VERSION 5.7 ;
  NOWIREEXTENSIONATPIN ON ;
  DIVIDERCHAR "/" ;
  BUSBITCHARS "[]" ;
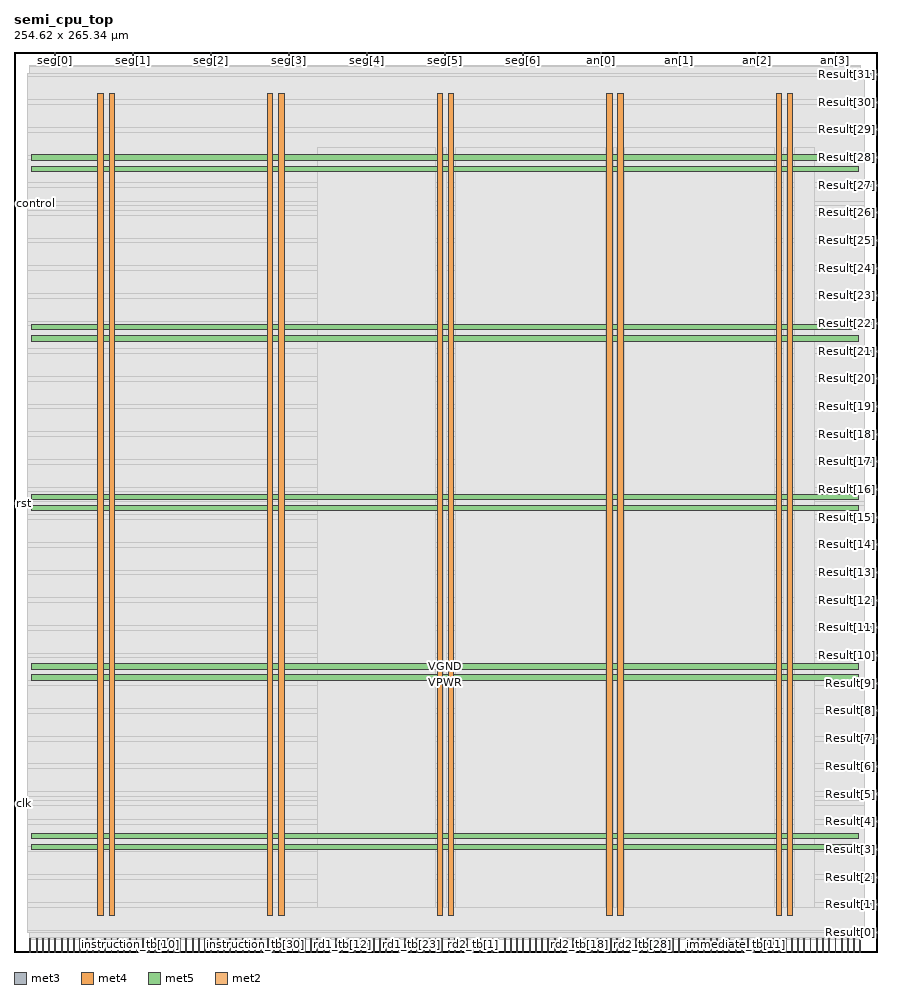
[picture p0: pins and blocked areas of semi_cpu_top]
MACRO semi_cpu_top
  CLASS BLOCK ;
  FOREIGN semi_cpu_top ;
  ORIGIN 0.000 0.000 ;
  SIZE 254.620 BY 265.340 ;
  PIN Result[0]
    DIRECTION OUTPUT ;
    USE SIGNAL ;
    ANTENNADIFFAREA 0.445500 ;
    PORT
      LAYER met3 ;
        RECT 250.620 5.480 254.620 6.080 ;
    END
  END Result[0]
  PIN Result[10]
    DIRECTION OUTPUT ;
    USE SIGNAL ;
    ANTENNADIFFAREA 0.445500 ;
    PORT
      LAYER met3 ;
        RECT 250.620 87.080 254.620 87.680 ;
    END
  END Result[10]
  PIN Result[11]
    DIRECTION OUTPUT ;
    USE SIGNAL ;
    ANTENNADIFFAREA 0.445500 ;
    PORT
      LAYER met3 ;
        RECT 250.620 95.240 254.620 95.840 ;
    END
  END Result[11]
  PIN Result[12]
    DIRECTION OUTPUT ;
    USE SIGNAL ;
    ANTENNADIFFAREA 0.445500 ;
    PORT
      LAYER met3 ;
        RECT 250.620 103.400 254.620 104.000 ;
    END
  END Result[12]
  PIN Result[13]
    DIRECTION OUTPUT ;
    USE SIGNAL ;
    ANTENNADIFFAREA 0.445500 ;
    PORT
      LAYER met3 ;
        RECT 250.620 111.560 254.620 112.160 ;
    END
  END Result[13]
  PIN Result[14]
    DIRECTION OUTPUT ;
    USE SIGNAL ;
    ANTENNADIFFAREA 0.445500 ;
    PORT
      LAYER met3 ;
        RECT 250.620 119.720 254.620 120.320 ;
    END
  END Result[14]
  PIN Result[15]
    DIRECTION OUTPUT ;
    USE SIGNAL ;
    ANTENNADIFFAREA 0.445500 ;
    PORT
      LAYER met3 ;
        RECT 250.620 127.880 254.620 128.480 ;
    END
  END Result[15]
  PIN Result[16]
    DIRECTION OUTPUT ;
    USE SIGNAL ;
    ANTENNADIFFAREA 0.445500 ;
    PORT
      LAYER met3 ;
        RECT 250.620 136.040 254.620 136.640 ;
    END
  END Result[16]
  PIN Result[17]
    DIRECTION OUTPUT ;
    USE SIGNAL ;
    ANTENNADIFFAREA 0.445500 ;
    PORT
      LAYER met3 ;
        RECT 250.620 144.200 254.620 144.800 ;
    END
  END Result[17]
  PIN Result[18]
    DIRECTION OUTPUT ;
    USE SIGNAL ;
    ANTENNADIFFAREA 0.445500 ;
    PORT
      LAYER met3 ;
        RECT 250.620 152.360 254.620 152.960 ;
    END
  END Result[18]
  PIN Result[19]
    DIRECTION OUTPUT ;
    USE SIGNAL ;
    ANTENNADIFFAREA 0.445500 ;
    PORT
      LAYER met3 ;
        RECT 250.620 160.520 254.620 161.120 ;
    END
  END Result[19]
  PIN Result[1]
    DIRECTION OUTPUT ;
    USE SIGNAL ;
    ANTENNADIFFAREA 0.445500 ;
    PORT
      LAYER met3 ;
        RECT 250.620 13.640 254.620 14.240 ;
    END
  END Result[1]
  PIN Result[20]
    DIRECTION OUTPUT ;
    USE SIGNAL ;
    ANTENNADIFFAREA 0.445500 ;
    PORT
      LAYER met3 ;
        RECT 250.620 168.680 254.620 169.280 ;
    END
  END Result[20]
  PIN Result[21]
    DIRECTION OUTPUT ;
    USE SIGNAL ;
    ANTENNADIFFAREA 0.445500 ;
    PORT
      LAYER met3 ;
        RECT 250.620 176.840 254.620 177.440 ;
    END
  END Result[21]
  PIN Result[22]
    DIRECTION OUTPUT ;
    USE SIGNAL ;
    ANTENNADIFFAREA 0.445500 ;
    PORT
      LAYER met3 ;
        RECT 250.620 185.000 254.620 185.600 ;
    END
  END Result[22]
  PIN Result[23]
    DIRECTION OUTPUT ;
    USE SIGNAL ;
    ANTENNADIFFAREA 0.445500 ;
    PORT
      LAYER met3 ;
        RECT 250.620 193.160 254.620 193.760 ;
    END
  END Result[23]
  PIN Result[24]
    DIRECTION OUTPUT ;
    USE SIGNAL ;
    ANTENNADIFFAREA 0.445500 ;
    PORT
      LAYER met3 ;
        RECT 250.620 201.320 254.620 201.920 ;
    END
  END Result[24]
  PIN Result[25]
    DIRECTION OUTPUT ;
    USE SIGNAL ;
    ANTENNADIFFAREA 0.445500 ;
    PORT
      LAYER met3 ;
        RECT 250.620 209.480 254.620 210.080 ;
    END
  END Result[25]
  PIN Result[26]
    DIRECTION OUTPUT ;
    USE SIGNAL ;
    ANTENNADIFFAREA 0.445500 ;
    PORT
      LAYER met3 ;
        RECT 250.620 217.640 254.620 218.240 ;
    END
  END Result[26]
  PIN Result[27]
    DIRECTION OUTPUT ;
    USE SIGNAL ;
    ANTENNADIFFAREA 0.445500 ;
    PORT
      LAYER met3 ;
        RECT 250.620 225.800 254.620 226.400 ;
    END
  END Result[27]
  PIN Result[28]
    DIRECTION OUTPUT ;
    USE SIGNAL ;
    ANTENNADIFFAREA 0.445500 ;
    PORT
      LAYER met3 ;
        RECT 250.620 233.960 254.620 234.560 ;
    END
  END Result[28]
  PIN Result[29]
    DIRECTION OUTPUT ;
    USE SIGNAL ;
    ANTENNADIFFAREA 0.445500 ;
    PORT
      LAYER met3 ;
        RECT 250.620 242.120 254.620 242.720 ;
    END
  END Result[29]
  PIN Result[2]
    DIRECTION OUTPUT ;
    USE SIGNAL ;
    ANTENNADIFFAREA 0.445500 ;
    PORT
      LAYER met3 ;
        RECT 250.620 21.800 254.620 22.400 ;
    END
  END Result[2]
  PIN Result[30]
    DIRECTION OUTPUT ;
    USE SIGNAL ;
    ANTENNADIFFAREA 0.445500 ;
    PORT
      LAYER met3 ;
        RECT 250.620 250.280 254.620 250.880 ;
    END
  END Result[30]
  PIN Result[31]
    DIRECTION OUTPUT ;
    USE SIGNAL ;
    ANTENNADIFFAREA 0.445500 ;
    PORT
      LAYER met3 ;
        RECT 250.620 258.440 254.620 259.040 ;
    END
  END Result[31]
  PIN Result[3]
    DIRECTION OUTPUT ;
    USE SIGNAL ;
    ANTENNADIFFAREA 0.445500 ;
    PORT
      LAYER met3 ;
        RECT 250.620 29.960 254.620 30.560 ;
    END
  END Result[3]
  PIN Result[4]
    DIRECTION OUTPUT ;
    USE SIGNAL ;
    ANTENNADIFFAREA 0.445500 ;
    PORT
      LAYER met3 ;
        RECT 250.620 38.120 254.620 38.720 ;
    END
  END Result[4]
  PIN Result[5]
    DIRECTION OUTPUT ;
    USE SIGNAL ;
    ANTENNADIFFAREA 0.445500 ;
    PORT
      LAYER met3 ;
        RECT 250.620 46.280 254.620 46.880 ;
    END
  END Result[5]
  PIN Result[6]
    DIRECTION OUTPUT ;
    USE SIGNAL ;
    ANTENNADIFFAREA 0.445500 ;
    PORT
      LAYER met3 ;
        RECT 250.620 54.440 254.620 55.040 ;
    END
  END Result[6]
  PIN Result[7]
    DIRECTION OUTPUT ;
    USE SIGNAL ;
    ANTENNADIFFAREA 0.445500 ;
    PORT
      LAYER met3 ;
        RECT 250.620 62.600 254.620 63.200 ;
    END
  END Result[7]
  PIN Result[8]
    DIRECTION OUTPUT ;
    USE SIGNAL ;
    ANTENNADIFFAREA 0.445500 ;
    PORT
      LAYER met3 ;
        RECT 250.620 70.760 254.620 71.360 ;
    END
  END Result[8]
  PIN Result[9]
    DIRECTION OUTPUT ;
    USE SIGNAL ;
    ANTENNADIFFAREA 0.445500 ;
    PORT
      LAYER met3 ;
        RECT 250.620 78.920 254.620 79.520 ;
    END
  END Result[9]
  PIN VGND
    DIRECTION INOUT ;
    USE GROUND ;
    PORT
      LAYER met4 ;
        RECT 28.020 10.640 29.620 253.200 ;
    END
    PORT
      LAYER met4 ;
        RECT 78.020 10.640 79.620 253.200 ;
    END
    PORT
      LAYER met4 ;
        RECT 128.020 10.640 129.620 253.200 ;
    END
    PORT
      LAYER met4 ;
        RECT 178.020 10.640 179.620 253.200 ;
    END
    PORT
      LAYER met4 ;
        RECT 228.020 10.640 229.620 253.200 ;
    END
    PORT
      LAYER met5 ;
        RECT 5.280 33.380 249.100 34.980 ;
    END
    PORT
      LAYER met5 ;
        RECT 5.280 83.380 249.100 84.980 ;
    END
    PORT
      LAYER met5 ;
        RECT 5.280 133.380 249.100 134.980 ;
    END
    PORT
      LAYER met5 ;
        RECT 5.280 183.380 249.100 184.980 ;
    END
    PORT
      LAYER met5 ;
        RECT 5.280 233.380 249.100 234.980 ;
    END
  END VGND
  PIN VPWR
    DIRECTION INOUT ;
    USE POWER ;
    PORT
      LAYER met4 ;
        RECT 24.720 10.640 26.320 253.200 ;
    END
    PORT
      LAYER met4 ;
        RECT 74.720 10.640 76.320 253.200 ;
    END
    PORT
      LAYER met4 ;
        RECT 124.720 10.640 126.320 253.200 ;
    END
    PORT
      LAYER met4 ;
        RECT 174.720 10.640 176.320 253.200 ;
    END
    PORT
      LAYER met4 ;
        RECT 224.720 10.640 226.320 253.200 ;
    END
    PORT
      LAYER met5 ;
        RECT 5.280 30.080 249.100 31.680 ;
    END
    PORT
      LAYER met5 ;
        RECT 5.280 80.080 249.100 81.680 ;
    END
    PORT
      LAYER met5 ;
        RECT 5.280 130.080 249.100 131.680 ;
    END
    PORT
      LAYER met5 ;
        RECT 5.280 180.080 249.100 181.680 ;
    END
    PORT
      LAYER met5 ;
        RECT 5.280 230.080 249.100 231.680 ;
    END
  END VPWR
  PIN alu_op_tb[0]
    DIRECTION OUTPUT ;
    USE SIGNAL ;
    ANTENNADIFFAREA 0.445500 ;
    PORT
      LAYER met2 ;
        RECT 10.210 0.000 10.490 4.000 ;
    END
  END alu_op_tb[0]
  PIN alu_op_tb[1]
    DIRECTION OUTPUT ;
    USE SIGNAL ;
    ANTENNADIFFAREA 0.445500 ;
    PORT
      LAYER met2 ;
        RECT 12.050 0.000 12.330 4.000 ;
    END
  END alu_op_tb[1]
  PIN alu_op_tb[2]
    DIRECTION OUTPUT ;
    USE SIGNAL ;
    ANTENNADIFFAREA 0.445500 ;
    PORT
      LAYER met2 ;
        RECT 13.890 0.000 14.170 4.000 ;
    END
  END alu_op_tb[2]
  PIN an[0]
    DIRECTION OUTPUT ;
    USE SIGNAL ;
    ANTENNADIFFAREA 0.795200 ;
    PORT
      LAYER met2 ;
        RECT 173.050 261.340 173.330 265.340 ;
    END
  END an[0]
  PIN an[1]
    DIRECTION OUTPUT ;
    USE SIGNAL ;
    ANTENNADIFFAREA 0.795200 ;
    PORT
      LAYER met2 ;
        RECT 196.050 261.340 196.330 265.340 ;
    END
  END an[1]
  PIN an[2]
    DIRECTION OUTPUT ;
    USE SIGNAL ;
    ANTENNADIFFAREA 0.795200 ;
    PORT
      LAYER met2 ;
        RECT 219.050 261.340 219.330 265.340 ;
    END
  END an[2]
  PIN an[3]
    DIRECTION OUTPUT ;
    USE SIGNAL ;
    ANTENNADIFFAREA 0.795200 ;
    PORT
      LAYER met2 ;
        RECT 242.050 261.340 242.330 265.340 ;
    END
  END an[3]
  PIN clk
    DIRECTION INPUT ;
    USE SIGNAL ;
    ANTENNAGATEAREA 0.852000 ;
    ANTENNADIFFAREA 0.434700 ;
    PORT
      LAYER met3 ;
        RECT 0.000 43.560 4.000 44.160 ;
    END
  END clk
  PIN control
    DIRECTION INPUT ;
    USE SIGNAL ;
    ANTENNAGATEAREA 0.495000 ;
    ANTENNADIFFAREA 0.434700 ;
    PORT
      LAYER met3 ;
        RECT 0.000 220.360 4.000 220.960 ;
    END
  END control
  PIN immediate_tb[0]
    DIRECTION OUTPUT ;
    USE SIGNAL ;
    ANTENNADIFFAREA 0.445500 ;
    PORT
      LAYER met2 ;
        RECT 192.370 0.000 192.650 4.000 ;
    END
  END immediate_tb[0]
  PIN immediate_tb[10]
    DIRECTION OUTPUT ;
    USE SIGNAL ;
    PORT
      LAYER met2 ;
        RECT 210.770 0.000 211.050 4.000 ;
    END
  END immediate_tb[10]
  PIN immediate_tb[11]
    DIRECTION OUTPUT ;
    USE SIGNAL ;
    PORT
      LAYER met2 ;
        RECT 212.610 0.000 212.890 4.000 ;
    END
  END immediate_tb[11]
  PIN immediate_tb[12]
    DIRECTION OUTPUT ;
    USE SIGNAL ;
    PORT
      LAYER met2 ;
        RECT 214.450 0.000 214.730 4.000 ;
    END
  END immediate_tb[12]
  PIN immediate_tb[13]
    DIRECTION OUTPUT ;
    USE SIGNAL ;
    PORT
      LAYER met2 ;
        RECT 216.290 0.000 216.570 4.000 ;
    END
  END immediate_tb[13]
  PIN immediate_tb[14]
    DIRECTION OUTPUT ;
    USE SIGNAL ;
    ANTENNADIFFAREA 0.445500 ;
    PORT
      LAYER met2 ;
        RECT 218.130 0.000 218.410 4.000 ;
    END
  END immediate_tb[14]
  PIN immediate_tb[15]
    DIRECTION OUTPUT ;
    USE SIGNAL ;
    ANTENNADIFFAREA 0.445500 ;
    PORT
      LAYER met2 ;
        RECT 219.970 0.000 220.250 4.000 ;
    END
  END immediate_tb[15]
  PIN immediate_tb[16]
    DIRECTION OUTPUT ;
    USE SIGNAL ;
    PORT
      LAYER met2 ;
        RECT 221.810 0.000 222.090 4.000 ;
    END
  END immediate_tb[16]
  PIN immediate_tb[17]
    DIRECTION OUTPUT ;
    USE SIGNAL ;
    PORT
      LAYER met2 ;
        RECT 223.650 0.000 223.930 4.000 ;
    END
  END immediate_tb[17]
  PIN immediate_tb[18]
    DIRECTION OUTPUT ;
    USE SIGNAL ;
    PORT
      LAYER met2 ;
        RECT 225.490 0.000 225.770 4.000 ;
    END
  END immediate_tb[18]
  PIN immediate_tb[19]
    DIRECTION OUTPUT ;
    USE SIGNAL ;
    PORT
      LAYER met2 ;
        RECT 227.330 0.000 227.610 4.000 ;
    END
  END immediate_tb[19]
  PIN immediate_tb[1]
    DIRECTION OUTPUT ;
    USE SIGNAL ;
    ANTENNADIFFAREA 0.445500 ;
    PORT
      LAYER met2 ;
        RECT 194.210 0.000 194.490 4.000 ;
    END
  END immediate_tb[1]
  PIN immediate_tb[20]
    DIRECTION OUTPUT ;
    USE SIGNAL ;
    PORT
      LAYER met2 ;
        RECT 229.170 0.000 229.450 4.000 ;
    END
  END immediate_tb[20]
  PIN immediate_tb[21]
    DIRECTION OUTPUT ;
    USE SIGNAL ;
    PORT
      LAYER met2 ;
        RECT 231.010 0.000 231.290 4.000 ;
    END
  END immediate_tb[21]
  PIN immediate_tb[22]
    DIRECTION OUTPUT ;
    USE SIGNAL ;
    PORT
      LAYER met2 ;
        RECT 232.850 0.000 233.130 4.000 ;
    END
  END immediate_tb[22]
  PIN immediate_tb[23]
    DIRECTION OUTPUT ;
    USE SIGNAL ;
    PORT
      LAYER met2 ;
        RECT 234.690 0.000 234.970 4.000 ;
    END
  END immediate_tb[23]
  PIN immediate_tb[24]
    DIRECTION OUTPUT ;
    USE SIGNAL ;
    PORT
      LAYER met2 ;
        RECT 236.530 0.000 236.810 4.000 ;
    END
  END immediate_tb[24]
  PIN immediate_tb[25]
    DIRECTION OUTPUT ;
    USE SIGNAL ;
    PORT
      LAYER met2 ;
        RECT 238.370 0.000 238.650 4.000 ;
    END
  END immediate_tb[25]
  PIN immediate_tb[26]
    DIRECTION OUTPUT ;
    USE SIGNAL ;
    PORT
      LAYER met2 ;
        RECT 240.210 0.000 240.490 4.000 ;
    END
  END immediate_tb[26]
  PIN immediate_tb[27]
    DIRECTION OUTPUT ;
    USE SIGNAL ;
    PORT
      LAYER met2 ;
        RECT 242.050 0.000 242.330 4.000 ;
    END
  END immediate_tb[27]
  PIN immediate_tb[28]
    DIRECTION OUTPUT ;
    USE SIGNAL ;
    PORT
      LAYER met2 ;
        RECT 243.890 0.000 244.170 4.000 ;
    END
  END immediate_tb[28]
  PIN immediate_tb[29]
    DIRECTION OUTPUT ;
    USE SIGNAL ;
    PORT
      LAYER met2 ;
        RECT 245.730 0.000 246.010 4.000 ;
    END
  END immediate_tb[29]
  PIN immediate_tb[2]
    DIRECTION OUTPUT ;
    USE SIGNAL ;
    ANTENNADIFFAREA 0.445500 ;
    PORT
      LAYER met2 ;
        RECT 196.050 0.000 196.330 4.000 ;
    END
  END immediate_tb[2]
  PIN immediate_tb[30]
    DIRECTION OUTPUT ;
    USE SIGNAL ;
    PORT
      LAYER met2 ;
        RECT 247.570 0.000 247.850 4.000 ;
    END
  END immediate_tb[30]
  PIN immediate_tb[31]
    DIRECTION OUTPUT ;
    USE SIGNAL ;
    PORT
      LAYER met2 ;
        RECT 249.410 0.000 249.690 4.000 ;
    END
  END immediate_tb[31]
  PIN immediate_tb[3]
    DIRECTION OUTPUT ;
    USE SIGNAL ;
    ANTENNADIFFAREA 0.445500 ;
    PORT
      LAYER met2 ;
        RECT 197.890 0.000 198.170 4.000 ;
    END
  END immediate_tb[3]
  PIN immediate_tb[4]
    DIRECTION OUTPUT ;
    USE SIGNAL ;
    PORT
      LAYER met2 ;
        RECT 199.730 0.000 200.010 4.000 ;
    END
  END immediate_tb[4]
  PIN immediate_tb[5]
    DIRECTION OUTPUT ;
    USE SIGNAL ;
    PORT
      LAYER met2 ;
        RECT 201.570 0.000 201.850 4.000 ;
    END
  END immediate_tb[5]
  PIN immediate_tb[6]
    DIRECTION OUTPUT ;
    USE SIGNAL ;
    PORT
      LAYER met2 ;
        RECT 203.410 0.000 203.690 4.000 ;
    END
  END immediate_tb[6]
  PIN immediate_tb[7]
    DIRECTION OUTPUT ;
    USE SIGNAL ;
    PORT
      LAYER met2 ;
        RECT 205.250 0.000 205.530 4.000 ;
    END
  END immediate_tb[7]
  PIN immediate_tb[8]
    DIRECTION OUTPUT ;
    USE SIGNAL ;
    PORT
      LAYER met2 ;
        RECT 207.090 0.000 207.370 4.000 ;
    END
  END immediate_tb[8]
  PIN immediate_tb[9]
    DIRECTION OUTPUT ;
    USE SIGNAL ;
    PORT
      LAYER met2 ;
        RECT 208.930 0.000 209.210 4.000 ;
    END
  END immediate_tb[9]
  PIN instruction_tb[0]
    DIRECTION OUTPUT ;
    USE SIGNAL ;
    ANTENNADIFFAREA 0.445500 ;
    PORT
      LAYER met2 ;
        RECT 15.730 0.000 16.010 4.000 ;
    END
  END instruction_tb[0]
  PIN instruction_tb[10]
    DIRECTION OUTPUT ;
    USE SIGNAL ;
    PORT
      LAYER met2 ;
        RECT 34.130 0.000 34.410 4.000 ;
    END
  END instruction_tb[10]
  PIN instruction_tb[11]
    DIRECTION OUTPUT ;
    USE SIGNAL ;
    PORT
      LAYER met2 ;
        RECT 35.970 0.000 36.250 4.000 ;
    END
  END instruction_tb[11]
  PIN instruction_tb[12]
    DIRECTION OUTPUT ;
    USE SIGNAL ;
    PORT
      LAYER met2 ;
        RECT 37.810 0.000 38.090 4.000 ;
    END
  END instruction_tb[12]
  PIN instruction_tb[13]
    DIRECTION OUTPUT ;
    USE SIGNAL ;
    PORT
      LAYER met2 ;
        RECT 39.650 0.000 39.930 4.000 ;
    END
  END instruction_tb[13]
  PIN instruction_tb[14]
    DIRECTION OUTPUT ;
    USE SIGNAL ;
    ANTENNADIFFAREA 0.445500 ;
    PORT
      LAYER met2 ;
        RECT 41.490 0.000 41.770 4.000 ;
    END
  END instruction_tb[14]
  PIN instruction_tb[15]
    DIRECTION OUTPUT ;
    USE SIGNAL ;
    ANTENNADIFFAREA 0.445500 ;
    PORT
      LAYER met2 ;
        RECT 43.330 0.000 43.610 4.000 ;
    END
  END instruction_tb[15]
  PIN instruction_tb[16]
    DIRECTION OUTPUT ;
    USE SIGNAL ;
    ANTENNADIFFAREA 0.445500 ;
    PORT
      LAYER met2 ;
        RECT 45.170 0.000 45.450 4.000 ;
    END
  END instruction_tb[16]
  PIN instruction_tb[17]
    DIRECTION OUTPUT ;
    USE SIGNAL ;
    ANTENNADIFFAREA 0.445500 ;
    PORT
      LAYER met2 ;
        RECT 47.010 0.000 47.290 4.000 ;
    END
  END instruction_tb[17]
  PIN instruction_tb[18]
    DIRECTION OUTPUT ;
    USE SIGNAL ;
    PORT
      LAYER met2 ;
        RECT 48.850 0.000 49.130 4.000 ;
    END
  END instruction_tb[18]
  PIN instruction_tb[19]
    DIRECTION OUTPUT ;
    USE SIGNAL ;
    ANTENNADIFFAREA 0.445500 ;
    PORT
      LAYER met2 ;
        RECT 50.690 0.000 50.970 4.000 ;
    END
  END instruction_tb[19]
  PIN instruction_tb[1]
    DIRECTION OUTPUT ;
    USE SIGNAL ;
    ANTENNADIFFAREA 0.445500 ;
    PORT
      LAYER met2 ;
        RECT 17.570 0.000 17.850 4.000 ;
    END
  END instruction_tb[1]
  PIN instruction_tb[20]
    DIRECTION OUTPUT ;
    USE SIGNAL ;
    ANTENNADIFFAREA 0.445500 ;
    PORT
      LAYER met2 ;
        RECT 52.530 0.000 52.810 4.000 ;
    END
  END instruction_tb[20]
  PIN instruction_tb[21]
    DIRECTION OUTPUT ;
    USE SIGNAL ;
    PORT
      LAYER met2 ;
        RECT 54.370 0.000 54.650 4.000 ;
    END
  END instruction_tb[21]
  PIN instruction_tb[22]
    DIRECTION OUTPUT ;
    USE SIGNAL ;
    ANTENNADIFFAREA 0.445500 ;
    PORT
      LAYER met2 ;
        RECT 56.210 0.000 56.490 4.000 ;
    END
  END instruction_tb[22]
  PIN instruction_tb[23]
    DIRECTION OUTPUT ;
    USE SIGNAL ;
    ANTENNADIFFAREA 0.445500 ;
    PORT
      LAYER met2 ;
        RECT 58.050 0.000 58.330 4.000 ;
    END
  END instruction_tb[23]
  PIN instruction_tb[24]
    DIRECTION OUTPUT ;
    USE SIGNAL ;
    ANTENNADIFFAREA 0.445500 ;
    PORT
      LAYER met2 ;
        RECT 59.890 0.000 60.170 4.000 ;
    END
  END instruction_tb[24]
  PIN instruction_tb[25]
    DIRECTION OUTPUT ;
    USE SIGNAL ;
    ANTENNADIFFAREA 0.445500 ;
    PORT
      LAYER met2 ;
        RECT 61.730 0.000 62.010 4.000 ;
    END
  END instruction_tb[25]
  PIN instruction_tb[26]
    DIRECTION OUTPUT ;
    USE SIGNAL ;
    ANTENNADIFFAREA 0.445500 ;
    PORT
      LAYER met2 ;
        RECT 63.570 0.000 63.850 4.000 ;
    END
  END instruction_tb[26]
  PIN instruction_tb[27]
    DIRECTION OUTPUT ;
    USE SIGNAL ;
    ANTENNADIFFAREA 0.445500 ;
    PORT
      LAYER met2 ;
        RECT 65.410 0.000 65.690 4.000 ;
    END
  END instruction_tb[27]
  PIN instruction_tb[28]
    DIRECTION OUTPUT ;
    USE SIGNAL ;
    ANTENNADIFFAREA 0.445500 ;
    PORT
      LAYER met2 ;
        RECT 67.250 0.000 67.530 4.000 ;
    END
  END instruction_tb[28]
  PIN instruction_tb[29]
    DIRECTION OUTPUT ;
    USE SIGNAL ;
    ANTENNADIFFAREA 0.445500 ;
    PORT
      LAYER met2 ;
        RECT 69.090 0.000 69.370 4.000 ;
    END
  END instruction_tb[29]
  PIN instruction_tb[2]
    DIRECTION OUTPUT ;
    USE SIGNAL ;
    ANTENNADIFFAREA 0.445500 ;
    PORT
      LAYER met2 ;
        RECT 19.410 0.000 19.690 4.000 ;
    END
  END instruction_tb[2]
  PIN instruction_tb[30]
    DIRECTION OUTPUT ;
    USE SIGNAL ;
    ANTENNADIFFAREA 0.445500 ;
    PORT
      LAYER met2 ;
        RECT 70.930 0.000 71.210 4.000 ;
    END
  END instruction_tb[30]
  PIN instruction_tb[31]
    DIRECTION OUTPUT ;
    USE SIGNAL ;
    ANTENNADIFFAREA 0.445500 ;
    PORT
      LAYER met2 ;
        RECT 72.770 0.000 73.050 4.000 ;
    END
  END instruction_tb[31]
  PIN instruction_tb[3]
    DIRECTION OUTPUT ;
    USE SIGNAL ;
    ANTENNADIFFAREA 0.445500 ;
    PORT
      LAYER met2 ;
        RECT 21.250 0.000 21.530 4.000 ;
    END
  END instruction_tb[3]
  PIN instruction_tb[4]
    DIRECTION OUTPUT ;
    USE SIGNAL ;
    PORT
      LAYER met2 ;
        RECT 23.090 0.000 23.370 4.000 ;
    END
  END instruction_tb[4]
  PIN instruction_tb[5]
    DIRECTION OUTPUT ;
    USE SIGNAL ;
    PORT
      LAYER met2 ;
        RECT 24.930 0.000 25.210 4.000 ;
    END
  END instruction_tb[5]
  PIN instruction_tb[6]
    DIRECTION OUTPUT ;
    USE SIGNAL ;
    PORT
      LAYER met2 ;
        RECT 26.770 0.000 27.050 4.000 ;
    END
  END instruction_tb[6]
  PIN instruction_tb[7]
    DIRECTION OUTPUT ;
    USE SIGNAL ;
    PORT
      LAYER met2 ;
        RECT 28.610 0.000 28.890 4.000 ;
    END
  END instruction_tb[7]
  PIN instruction_tb[8]
    DIRECTION OUTPUT ;
    USE SIGNAL ;
    PORT
      LAYER met2 ;
        RECT 30.450 0.000 30.730 4.000 ;
    END
  END instruction_tb[8]
  PIN instruction_tb[9]
    DIRECTION OUTPUT ;
    USE SIGNAL ;
    PORT
      LAYER met2 ;
        RECT 32.290 0.000 32.570 4.000 ;
    END
  END instruction_tb[9]
  PIN pc_out_tb[0]
    DIRECTION OUTPUT ;
    USE SIGNAL ;
    ANTENNADIFFAREA 0.795200 ;
    PORT
      LAYER met2 ;
        RECT 4.690 0.000 4.970 4.000 ;
    END
  END pc_out_tb[0]
  PIN pc_out_tb[1]
    DIRECTION OUTPUT ;
    USE SIGNAL ;
    ANTENNADIFFAREA 0.445500 ;
    PORT
      LAYER met2 ;
        RECT 6.530 0.000 6.810 4.000 ;
    END
  END pc_out_tb[1]
  PIN pc_out_tb[2]
    DIRECTION OUTPUT ;
    USE SIGNAL ;
    ANTENNADIFFAREA 0.445500 ;
    PORT
      LAYER met2 ;
        RECT 8.370 0.000 8.650 4.000 ;
    END
  END pc_out_tb[2]
  PIN rd1_tb[0]
    DIRECTION OUTPUT ;
    USE SIGNAL ;
    ANTENNADIFFAREA 0.445500 ;
    PORT
      LAYER met2 ;
        RECT 74.610 0.000 74.890 4.000 ;
    END
  END rd1_tb[0]
  PIN rd1_tb[10]
    DIRECTION OUTPUT ;
    USE SIGNAL ;
    ANTENNADIFFAREA 0.445500 ;
    PORT
      LAYER met2 ;
        RECT 93.010 0.000 93.290 4.000 ;
    END
  END rd1_tb[10]
  PIN rd1_tb[11]
    DIRECTION OUTPUT ;
    USE SIGNAL ;
    ANTENNADIFFAREA 0.445500 ;
    PORT
      LAYER met2 ;
        RECT 94.850 0.000 95.130 4.000 ;
    END
  END rd1_tb[11]
  PIN rd1_tb[12]
    DIRECTION OUTPUT ;
    USE SIGNAL ;
    ANTENNADIFFAREA 0.445500 ;
    PORT
      LAYER met2 ;
        RECT 96.690 0.000 96.970 4.000 ;
    END
  END rd1_tb[12]
  PIN rd1_tb[13]
    DIRECTION OUTPUT ;
    USE SIGNAL ;
    ANTENNADIFFAREA 0.445500 ;
    PORT
      LAYER met2 ;
        RECT 98.530 0.000 98.810 4.000 ;
    END
  END rd1_tb[13]
  PIN rd1_tb[14]
    DIRECTION OUTPUT ;
    USE SIGNAL ;
    ANTENNADIFFAREA 0.445500 ;
    PORT
      LAYER met2 ;
        RECT 100.370 0.000 100.650 4.000 ;
    END
  END rd1_tb[14]
  PIN rd1_tb[15]
    DIRECTION OUTPUT ;
    USE SIGNAL ;
    ANTENNADIFFAREA 0.445500 ;
    PORT
      LAYER met2 ;
        RECT 102.210 0.000 102.490 4.000 ;
    END
  END rd1_tb[15]
  PIN rd1_tb[16]
    DIRECTION OUTPUT ;
    USE SIGNAL ;
    ANTENNADIFFAREA 0.445500 ;
    PORT
      LAYER met2 ;
        RECT 104.050 0.000 104.330 4.000 ;
    END
  END rd1_tb[16]
  PIN rd1_tb[17]
    DIRECTION OUTPUT ;
    USE SIGNAL ;
    ANTENNADIFFAREA 0.445500 ;
    PORT
      LAYER met2 ;
        RECT 105.890 0.000 106.170 4.000 ;
    END
  END rd1_tb[17]
  PIN rd1_tb[18]
    DIRECTION OUTPUT ;
    USE SIGNAL ;
    ANTENNADIFFAREA 0.445500 ;
    PORT
      LAYER met2 ;
        RECT 107.730 0.000 108.010 4.000 ;
    END
  END rd1_tb[18]
  PIN rd1_tb[19]
    DIRECTION OUTPUT ;
    USE SIGNAL ;
    ANTENNADIFFAREA 0.445500 ;
    PORT
      LAYER met2 ;
        RECT 109.570 0.000 109.850 4.000 ;
    END
  END rd1_tb[19]
  PIN rd1_tb[1]
    DIRECTION OUTPUT ;
    USE SIGNAL ;
    ANTENNADIFFAREA 0.445500 ;
    PORT
      LAYER met2 ;
        RECT 76.450 0.000 76.730 4.000 ;
    END
  END rd1_tb[1]
  PIN rd1_tb[20]
    DIRECTION OUTPUT ;
    USE SIGNAL ;
    ANTENNADIFFAREA 0.445500 ;
    PORT
      LAYER met2 ;
        RECT 111.410 0.000 111.690 4.000 ;
    END
  END rd1_tb[20]
  PIN rd1_tb[21]
    DIRECTION OUTPUT ;
    USE SIGNAL ;
    ANTENNADIFFAREA 0.445500 ;
    PORT
      LAYER met2 ;
        RECT 113.250 0.000 113.530 4.000 ;
    END
  END rd1_tb[21]
  PIN rd1_tb[22]
    DIRECTION OUTPUT ;
    USE SIGNAL ;
    ANTENNADIFFAREA 0.445500 ;
    PORT
      LAYER met2 ;
        RECT 115.090 0.000 115.370 4.000 ;
    END
  END rd1_tb[22]
  PIN rd1_tb[23]
    DIRECTION OUTPUT ;
    USE SIGNAL ;
    ANTENNADIFFAREA 0.445500 ;
    PORT
      LAYER met2 ;
        RECT 116.930 0.000 117.210 4.000 ;
    END
  END rd1_tb[23]
  PIN rd1_tb[24]
    DIRECTION OUTPUT ;
    USE SIGNAL ;
    ANTENNADIFFAREA 0.445500 ;
    PORT
      LAYER met2 ;
        RECT 118.770 0.000 119.050 4.000 ;
    END
  END rd1_tb[24]
  PIN rd1_tb[25]
    DIRECTION OUTPUT ;
    USE SIGNAL ;
    ANTENNADIFFAREA 0.445500 ;
    PORT
      LAYER met2 ;
        RECT 120.610 0.000 120.890 4.000 ;
    END
  END rd1_tb[25]
  PIN rd1_tb[26]
    DIRECTION OUTPUT ;
    USE SIGNAL ;
    ANTENNADIFFAREA 0.445500 ;
    PORT
      LAYER met2 ;
        RECT 122.450 0.000 122.730 4.000 ;
    END
  END rd1_tb[26]
  PIN rd1_tb[27]
    DIRECTION OUTPUT ;
    USE SIGNAL ;
    ANTENNADIFFAREA 0.445500 ;
    PORT
      LAYER met2 ;
        RECT 124.290 0.000 124.570 4.000 ;
    END
  END rd1_tb[27]
  PIN rd1_tb[28]
    DIRECTION OUTPUT ;
    USE SIGNAL ;
    ANTENNADIFFAREA 0.445500 ;
    PORT
      LAYER met2 ;
        RECT 126.130 0.000 126.410 4.000 ;
    END
  END rd1_tb[28]
  PIN rd1_tb[29]
    DIRECTION OUTPUT ;
    USE SIGNAL ;
    ANTENNADIFFAREA 0.445500 ;
    PORT
      LAYER met2 ;
        RECT 127.970 0.000 128.250 4.000 ;
    END
  END rd1_tb[29]
  PIN rd1_tb[2]
    DIRECTION OUTPUT ;
    USE SIGNAL ;
    ANTENNADIFFAREA 0.445500 ;
    PORT
      LAYER met2 ;
        RECT 78.290 0.000 78.570 4.000 ;
    END
  END rd1_tb[2]
  PIN rd1_tb[30]
    DIRECTION OUTPUT ;
    USE SIGNAL ;
    ANTENNADIFFAREA 0.445500 ;
    PORT
      LAYER met2 ;
        RECT 129.810 0.000 130.090 4.000 ;
    END
  END rd1_tb[30]
  PIN rd1_tb[31]
    DIRECTION OUTPUT ;
    USE SIGNAL ;
    ANTENNADIFFAREA 0.445500 ;
    PORT
      LAYER met2 ;
        RECT 131.650 0.000 131.930 4.000 ;
    END
  END rd1_tb[31]
  PIN rd1_tb[3]
    DIRECTION OUTPUT ;
    USE SIGNAL ;
    ANTENNADIFFAREA 0.445500 ;
    PORT
      LAYER met2 ;
        RECT 80.130 0.000 80.410 4.000 ;
    END
  END rd1_tb[3]
  PIN rd1_tb[4]
    DIRECTION OUTPUT ;
    USE SIGNAL ;
    ANTENNADIFFAREA 0.445500 ;
    PORT
      LAYER met2 ;
        RECT 81.970 0.000 82.250 4.000 ;
    END
  END rd1_tb[4]
  PIN rd1_tb[5]
    DIRECTION OUTPUT ;
    USE SIGNAL ;
    ANTENNADIFFAREA 0.445500 ;
    PORT
      LAYER met2 ;
        RECT 83.810 0.000 84.090 4.000 ;
    END
  END rd1_tb[5]
  PIN rd1_tb[6]
    DIRECTION OUTPUT ;
    USE SIGNAL ;
    ANTENNADIFFAREA 0.445500 ;
    PORT
      LAYER met2 ;
        RECT 85.650 0.000 85.930 4.000 ;
    END
  END rd1_tb[6]
  PIN rd1_tb[7]
    DIRECTION OUTPUT ;
    USE SIGNAL ;
    ANTENNADIFFAREA 0.445500 ;
    PORT
      LAYER met2 ;
        RECT 87.490 0.000 87.770 4.000 ;
    END
  END rd1_tb[7]
  PIN rd1_tb[8]
    DIRECTION OUTPUT ;
    USE SIGNAL ;
    ANTENNADIFFAREA 0.445500 ;
    PORT
      LAYER met2 ;
        RECT 89.330 0.000 89.610 4.000 ;
    END
  END rd1_tb[8]
  PIN rd1_tb[9]
    DIRECTION OUTPUT ;
    USE SIGNAL ;
    ANTENNADIFFAREA 0.445500 ;
    PORT
      LAYER met2 ;
        RECT 91.170 0.000 91.450 4.000 ;
    END
  END rd1_tb[9]
  PIN rd2_tb[0]
    DIRECTION OUTPUT ;
    USE SIGNAL ;
    ANTENNADIFFAREA 0.445500 ;
    PORT
      LAYER met2 ;
        RECT 133.490 0.000 133.770 4.000 ;
    END
  END rd2_tb[0]
  PIN rd2_tb[10]
    DIRECTION OUTPUT ;
    USE SIGNAL ;
    ANTENNADIFFAREA 0.445500 ;
    PORT
      LAYER met2 ;
        RECT 151.890 0.000 152.170 4.000 ;
    END
  END rd2_tb[10]
  PIN rd2_tb[11]
    DIRECTION OUTPUT ;
    USE SIGNAL ;
    ANTENNADIFFAREA 0.445500 ;
    PORT
      LAYER met2 ;
        RECT 153.730 0.000 154.010 4.000 ;
    END
  END rd2_tb[11]
  PIN rd2_tb[12]
    DIRECTION OUTPUT ;
    USE SIGNAL ;
    ANTENNADIFFAREA 0.445500 ;
    PORT
      LAYER met2 ;
        RECT 155.570 0.000 155.850 4.000 ;
    END
  END rd2_tb[12]
  PIN rd2_tb[13]
    DIRECTION OUTPUT ;
    USE SIGNAL ;
    ANTENNADIFFAREA 0.445500 ;
    PORT
      LAYER met2 ;
        RECT 157.410 0.000 157.690 4.000 ;
    END
  END rd2_tb[13]
  PIN rd2_tb[14]
    DIRECTION OUTPUT ;
    USE SIGNAL ;
    ANTENNADIFFAREA 0.445500 ;
    PORT
      LAYER met2 ;
        RECT 159.250 0.000 159.530 4.000 ;
    END
  END rd2_tb[14]
  PIN rd2_tb[15]
    DIRECTION OUTPUT ;
    USE SIGNAL ;
    ANTENNADIFFAREA 0.445500 ;
    PORT
      LAYER met2 ;
        RECT 161.090 0.000 161.370 4.000 ;
    END
  END rd2_tb[15]
  PIN rd2_tb[16]
    DIRECTION OUTPUT ;
    USE SIGNAL ;
    ANTENNADIFFAREA 0.445500 ;
    PORT
      LAYER met2 ;
        RECT 162.930 0.000 163.210 4.000 ;
    END
  END rd2_tb[16]
  PIN rd2_tb[17]
    DIRECTION OUTPUT ;
    USE SIGNAL ;
    ANTENNADIFFAREA 0.445500 ;
    PORT
      LAYER met2 ;
        RECT 164.770 0.000 165.050 4.000 ;
    END
  END rd2_tb[17]
  PIN rd2_tb[18]
    DIRECTION OUTPUT ;
    USE SIGNAL ;
    ANTENNADIFFAREA 0.445500 ;
    PORT
      LAYER met2 ;
        RECT 166.610 0.000 166.890 4.000 ;
    END
  END rd2_tb[18]
  PIN rd2_tb[19]
    DIRECTION OUTPUT ;
    USE SIGNAL ;
    ANTENNADIFFAREA 0.445500 ;
    PORT
      LAYER met2 ;
        RECT 168.450 0.000 168.730 4.000 ;
    END
  END rd2_tb[19]
  PIN rd2_tb[1]
    DIRECTION OUTPUT ;
    USE SIGNAL ;
    ANTENNADIFFAREA 0.445500 ;
    PORT
      LAYER met2 ;
        RECT 135.330 0.000 135.610 4.000 ;
    END
  END rd2_tb[1]
  PIN rd2_tb[20]
    DIRECTION OUTPUT ;
    USE SIGNAL ;
    ANTENNADIFFAREA 0.445500 ;
    PORT
      LAYER met2 ;
        RECT 170.290 0.000 170.570 4.000 ;
    END
  END rd2_tb[20]
  PIN rd2_tb[21]
    DIRECTION OUTPUT ;
    USE SIGNAL ;
    ANTENNADIFFAREA 0.445500 ;
    PORT
      LAYER met2 ;
        RECT 172.130 0.000 172.410 4.000 ;
    END
  END rd2_tb[21]
  PIN rd2_tb[22]
    DIRECTION OUTPUT ;
    USE SIGNAL ;
    ANTENNADIFFAREA 0.445500 ;
    PORT
      LAYER met2 ;
        RECT 173.970 0.000 174.250 4.000 ;
    END
  END rd2_tb[22]
  PIN rd2_tb[23]
    DIRECTION OUTPUT ;
    USE SIGNAL ;
    ANTENNADIFFAREA 0.445500 ;
    PORT
      LAYER met2 ;
        RECT 175.810 0.000 176.090 4.000 ;
    END
  END rd2_tb[23]
  PIN rd2_tb[24]
    DIRECTION OUTPUT ;
    USE SIGNAL ;
    ANTENNADIFFAREA 0.445500 ;
    PORT
      LAYER met2 ;
        RECT 177.650 0.000 177.930 4.000 ;
    END
  END rd2_tb[24]
  PIN rd2_tb[25]
    DIRECTION OUTPUT ;
    USE SIGNAL ;
    ANTENNADIFFAREA 0.445500 ;
    PORT
      LAYER met2 ;
        RECT 179.490 0.000 179.770 4.000 ;
    END
  END rd2_tb[25]
  PIN rd2_tb[26]
    DIRECTION OUTPUT ;
    USE SIGNAL ;
    ANTENNADIFFAREA 0.445500 ;
    PORT
      LAYER met2 ;
        RECT 181.330 0.000 181.610 4.000 ;
    END
  END rd2_tb[26]
  PIN rd2_tb[27]
    DIRECTION OUTPUT ;
    USE SIGNAL ;
    ANTENNADIFFAREA 0.445500 ;
    PORT
      LAYER met2 ;
        RECT 183.170 0.000 183.450 4.000 ;
    END
  END rd2_tb[27]
  PIN rd2_tb[28]
    DIRECTION OUTPUT ;
    USE SIGNAL ;
    ANTENNADIFFAREA 0.445500 ;
    PORT
      LAYER met2 ;
        RECT 185.010 0.000 185.290 4.000 ;
    END
  END rd2_tb[28]
  PIN rd2_tb[29]
    DIRECTION OUTPUT ;
    USE SIGNAL ;
    ANTENNADIFFAREA 0.445500 ;
    PORT
      LAYER met2 ;
        RECT 186.850 0.000 187.130 4.000 ;
    END
  END rd2_tb[29]
  PIN rd2_tb[2]
    DIRECTION OUTPUT ;
    USE SIGNAL ;
    ANTENNADIFFAREA 0.445500 ;
    PORT
      LAYER met2 ;
        RECT 137.170 0.000 137.450 4.000 ;
    END
  END rd2_tb[2]
  PIN rd2_tb[30]
    DIRECTION OUTPUT ;
    USE SIGNAL ;
    ANTENNADIFFAREA 0.445500 ;
    PORT
      LAYER met2 ;
        RECT 188.690 0.000 188.970 4.000 ;
    END
  END rd2_tb[30]
  PIN rd2_tb[31]
    DIRECTION OUTPUT ;
    USE SIGNAL ;
    ANTENNADIFFAREA 0.445500 ;
    PORT
      LAYER met2 ;
        RECT 190.530 0.000 190.810 4.000 ;
    END
  END rd2_tb[31]
  PIN rd2_tb[3]
    DIRECTION OUTPUT ;
    USE SIGNAL ;
    ANTENNADIFFAREA 0.445500 ;
    PORT
      LAYER met2 ;
        RECT 139.010 0.000 139.290 4.000 ;
    END
  END rd2_tb[3]
  PIN rd2_tb[4]
    DIRECTION OUTPUT ;
    USE SIGNAL ;
    ANTENNADIFFAREA 0.445500 ;
    PORT
      LAYER met2 ;
        RECT 140.850 0.000 141.130 4.000 ;
    END
  END rd2_tb[4]
  PIN rd2_tb[5]
    DIRECTION OUTPUT ;
    USE SIGNAL ;
    ANTENNADIFFAREA 0.445500 ;
    PORT
      LAYER met2 ;
        RECT 142.690 0.000 142.970 4.000 ;
    END
  END rd2_tb[5]
  PIN rd2_tb[6]
    DIRECTION OUTPUT ;
    USE SIGNAL ;
    ANTENNADIFFAREA 0.445500 ;
    PORT
      LAYER met2 ;
        RECT 144.530 0.000 144.810 4.000 ;
    END
  END rd2_tb[6]
  PIN rd2_tb[7]
    DIRECTION OUTPUT ;
    USE SIGNAL ;
    ANTENNADIFFAREA 0.445500 ;
    PORT
      LAYER met2 ;
        RECT 146.370 0.000 146.650 4.000 ;
    END
  END rd2_tb[7]
  PIN rd2_tb[8]
    DIRECTION OUTPUT ;
    USE SIGNAL ;
    ANTENNADIFFAREA 0.445500 ;
    PORT
      LAYER met2 ;
        RECT 148.210 0.000 148.490 4.000 ;
    END
  END rd2_tb[8]
  PIN rd2_tb[9]
    DIRECTION OUTPUT ;
    USE SIGNAL ;
    ANTENNADIFFAREA 0.445500 ;
    PORT
      LAYER met2 ;
        RECT 150.050 0.000 150.330 4.000 ;
    END
  END rd2_tb[9]
  PIN rst
    DIRECTION INPUT ;
    USE SIGNAL ;
    ANTENNAGATEAREA 0.748500 ;
    ANTENNADIFFAREA 1.738800 ;
    PORT
      LAYER met3 ;
        RECT 0.000 131.960 4.000 132.560 ;
    END
  END rst
  PIN seg[0]
    DIRECTION OUTPUT ;
    USE SIGNAL ;
    ANTENNADIFFAREA 0.795200 ;
    PORT
      LAYER met2 ;
        RECT 12.050 261.340 12.330 265.340 ;
    END
  END seg[0]
  PIN seg[1]
    DIRECTION OUTPUT ;
    USE SIGNAL ;
    ANTENNADIFFAREA 0.795200 ;
    PORT
      LAYER met2 ;
        RECT 35.050 261.340 35.330 265.340 ;
    END
  END seg[1]
  PIN seg[2]
    DIRECTION OUTPUT ;
    USE SIGNAL ;
    ANTENNADIFFAREA 0.795200 ;
    PORT
      LAYER met2 ;
        RECT 58.050 261.340 58.330 265.340 ;
    END
  END seg[2]
  PIN seg[3]
    DIRECTION OUTPUT ;
    USE SIGNAL ;
    ANTENNADIFFAREA 0.795200 ;
    PORT
      LAYER met2 ;
        RECT 81.050 261.340 81.330 265.340 ;
    END
  END seg[3]
  PIN seg[4]
    DIRECTION OUTPUT ;
    USE SIGNAL ;
    ANTENNADIFFAREA 0.795200 ;
    PORT
      LAYER met2 ;
        RECT 104.050 261.340 104.330 265.340 ;
    END
  END seg[4]
  PIN seg[5]
    DIRECTION OUTPUT ;
    USE SIGNAL ;
    ANTENNADIFFAREA 0.795200 ;
    PORT
      LAYER met2 ;
        RECT 127.050 261.340 127.330 265.340 ;
    END
  END seg[5]
  PIN seg[6]
    DIRECTION OUTPUT ;
    USE SIGNAL ;
    ANTENNADIFFAREA 0.795200 ;
    PORT
      LAYER met2 ;
        RECT 150.050 261.340 150.330 265.340 ;
    END
  END seg[6]
  OBS
      LAYER nwell ;
        RECT 5.330 10.795 249.050 253.150 ;
      LAYER li1 ;
        RECT 5.520 10.795 248.860 253.045 ;
      LAYER met1 ;
        RECT 4.670 6.840 249.710 253.200 ;
      LAYER met2 ;
        RECT 4.700 261.060 11.770 261.340 ;
        RECT 12.610 261.060 34.770 261.340 ;
        RECT 35.610 261.060 57.770 261.340 ;
        RECT 58.610 261.060 80.770 261.340 ;
        RECT 81.610 261.060 103.770 261.340 ;
        RECT 104.610 261.060 126.770 261.340 ;
        RECT 127.610 261.060 149.770 261.340 ;
        RECT 150.610 261.060 172.770 261.340 ;
        RECT 173.610 261.060 195.770 261.340 ;
        RECT 196.610 261.060 218.770 261.340 ;
        RECT 219.610 261.060 241.770 261.340 ;
        RECT 242.610 261.060 249.680 261.340 ;
        RECT 4.700 4.280 249.680 261.060 ;
        RECT 5.250 3.670 6.250 4.280 ;
        RECT 7.090 3.670 8.090 4.280 ;
        RECT 8.930 3.670 9.930 4.280 ;
        RECT 10.770 3.670 11.770 4.280 ;
        RECT 12.610 3.670 13.610 4.280 ;
        RECT 14.450 3.670 15.450 4.280 ;
        RECT 16.290 3.670 17.290 4.280 ;
        RECT 18.130 3.670 19.130 4.280 ;
        RECT 19.970 3.670 20.970 4.280 ;
        RECT 21.810 3.670 22.810 4.280 ;
        RECT 23.650 3.670 24.650 4.280 ;
        RECT 25.490 3.670 26.490 4.280 ;
        RECT 27.330 3.670 28.330 4.280 ;
        RECT 29.170 3.670 30.170 4.280 ;
        RECT 31.010 3.670 32.010 4.280 ;
        RECT 32.850 3.670 33.850 4.280 ;
        RECT 34.690 3.670 35.690 4.280 ;
        RECT 36.530 3.670 37.530 4.280 ;
        RECT 38.370 3.670 39.370 4.280 ;
        RECT 40.210 3.670 41.210 4.280 ;
        RECT 42.050 3.670 43.050 4.280 ;
        RECT 43.890 3.670 44.890 4.280 ;
        RECT 45.730 3.670 46.730 4.280 ;
        RECT 47.570 3.670 48.570 4.280 ;
        RECT 49.410 3.670 50.410 4.280 ;
        RECT 51.250 3.670 52.250 4.280 ;
        RECT 53.090 3.670 54.090 4.280 ;
        RECT 54.930 3.670 55.930 4.280 ;
        RECT 56.770 3.670 57.770 4.280 ;
        RECT 58.610 3.670 59.610 4.280 ;
        RECT 60.450 3.670 61.450 4.280 ;
        RECT 62.290 3.670 63.290 4.280 ;
        RECT 64.130 3.670 65.130 4.280 ;
        RECT 65.970 3.670 66.970 4.280 ;
        RECT 67.810 3.670 68.810 4.280 ;
        RECT 69.650 3.670 70.650 4.280 ;
        RECT 71.490 3.670 72.490 4.280 ;
        RECT 73.330 3.670 74.330 4.280 ;
        RECT 75.170 3.670 76.170 4.280 ;
        RECT 77.010 3.670 78.010 4.280 ;
        RECT 78.850 3.670 79.850 4.280 ;
        RECT 80.690 3.670 81.690 4.280 ;
        RECT 82.530 3.670 83.530 4.280 ;
        RECT 84.370 3.670 85.370 4.280 ;
        RECT 86.210 3.670 87.210 4.280 ;
        RECT 88.050 3.670 89.050 4.280 ;
        RECT 89.890 3.670 90.890 4.280 ;
        RECT 91.730 3.670 92.730 4.280 ;
        RECT 93.570 3.670 94.570 4.280 ;
        RECT 95.410 3.670 96.410 4.280 ;
        RECT 97.250 3.670 98.250 4.280 ;
        RECT 99.090 3.670 100.090 4.280 ;
        RECT 100.930 3.670 101.930 4.280 ;
        RECT 102.770 3.670 103.770 4.280 ;
        RECT 104.610 3.670 105.610 4.280 ;
        RECT 106.450 3.670 107.450 4.280 ;
        RECT 108.290 3.670 109.290 4.280 ;
        RECT 110.130 3.670 111.130 4.280 ;
        RECT 111.970 3.670 112.970 4.280 ;
        RECT 113.810 3.670 114.810 4.280 ;
        RECT 115.650 3.670 116.650 4.280 ;
        RECT 117.490 3.670 118.490 4.280 ;
        RECT 119.330 3.670 120.330 4.280 ;
        RECT 121.170 3.670 122.170 4.280 ;
        RECT 123.010 3.670 124.010 4.280 ;
        RECT 124.850 3.670 125.850 4.280 ;
        RECT 126.690 3.670 127.690 4.280 ;
        RECT 128.530 3.670 129.530 4.280 ;
        RECT 130.370 3.670 131.370 4.280 ;
        RECT 132.210 3.670 133.210 4.280 ;
        RECT 134.050 3.670 135.050 4.280 ;
        RECT 135.890 3.670 136.890 4.280 ;
        RECT 137.730 3.670 138.730 4.280 ;
        RECT 139.570 3.670 140.570 4.280 ;
        RECT 141.410 3.670 142.410 4.280 ;
        RECT 143.250 3.670 144.250 4.280 ;
        RECT 145.090 3.670 146.090 4.280 ;
        RECT 146.930 3.670 147.930 4.280 ;
        RECT 148.770 3.670 149.770 4.280 ;
        RECT 150.610 3.670 151.610 4.280 ;
        RECT 152.450 3.670 153.450 4.280 ;
        RECT 154.290 3.670 155.290 4.280 ;
        RECT 156.130 3.670 157.130 4.280 ;
        RECT 157.970 3.670 158.970 4.280 ;
        RECT 159.810 3.670 160.810 4.280 ;
        RECT 161.650 3.670 162.650 4.280 ;
        RECT 163.490 3.670 164.490 4.280 ;
        RECT 165.330 3.670 166.330 4.280 ;
        RECT 167.170 3.670 168.170 4.280 ;
        RECT 169.010 3.670 170.010 4.280 ;
        RECT 170.850 3.670 171.850 4.280 ;
        RECT 172.690 3.670 173.690 4.280 ;
        RECT 174.530 3.670 175.530 4.280 ;
        RECT 176.370 3.670 177.370 4.280 ;
        RECT 178.210 3.670 179.210 4.280 ;
        RECT 180.050 3.670 181.050 4.280 ;
        RECT 181.890 3.670 182.890 4.280 ;
        RECT 183.730 3.670 184.730 4.280 ;
        RECT 185.570 3.670 186.570 4.280 ;
        RECT 187.410 3.670 188.410 4.280 ;
        RECT 189.250 3.670 190.250 4.280 ;
        RECT 191.090 3.670 192.090 4.280 ;
        RECT 192.930 3.670 193.930 4.280 ;
        RECT 194.770 3.670 195.770 4.280 ;
        RECT 196.610 3.670 197.610 4.280 ;
        RECT 198.450 3.670 199.450 4.280 ;
        RECT 200.290 3.670 201.290 4.280 ;
        RECT 202.130 3.670 203.130 4.280 ;
        RECT 203.970 3.670 204.970 4.280 ;
        RECT 205.810 3.670 206.810 4.280 ;
        RECT 207.650 3.670 208.650 4.280 ;
        RECT 209.490 3.670 210.490 4.280 ;
        RECT 211.330 3.670 212.330 4.280 ;
        RECT 213.170 3.670 214.170 4.280 ;
        RECT 215.010 3.670 216.010 4.280 ;
        RECT 216.850 3.670 217.850 4.280 ;
        RECT 218.690 3.670 219.690 4.280 ;
        RECT 220.530 3.670 221.530 4.280 ;
        RECT 222.370 3.670 223.370 4.280 ;
        RECT 224.210 3.670 225.210 4.280 ;
        RECT 226.050 3.670 227.050 4.280 ;
        RECT 227.890 3.670 228.890 4.280 ;
        RECT 229.730 3.670 230.730 4.280 ;
        RECT 231.570 3.670 232.570 4.280 ;
        RECT 233.410 3.670 234.410 4.280 ;
        RECT 235.250 3.670 236.250 4.280 ;
        RECT 237.090 3.670 238.090 4.280 ;
        RECT 238.930 3.670 239.930 4.280 ;
        RECT 240.770 3.670 241.770 4.280 ;
        RECT 242.610 3.670 243.610 4.280 ;
        RECT 244.450 3.670 245.450 4.280 ;
        RECT 246.290 3.670 247.290 4.280 ;
        RECT 248.130 3.670 249.130 4.280 ;
      LAYER met3 ;
        RECT 4.000 258.040 250.220 258.905 ;
        RECT 4.000 251.280 250.620 258.040 ;
        RECT 4.000 249.880 250.220 251.280 ;
        RECT 4.000 243.120 250.620 249.880 ;
        RECT 4.000 241.720 250.220 243.120 ;
        RECT 4.000 234.960 250.620 241.720 ;
        RECT 4.000 233.560 250.220 234.960 ;
        RECT 4.000 226.800 250.620 233.560 ;
        RECT 4.000 225.400 250.220 226.800 ;
        RECT 4.000 221.360 250.620 225.400 ;
        RECT 4.400 219.960 250.620 221.360 ;
        RECT 4.000 218.640 250.620 219.960 ;
        RECT 4.000 217.240 250.220 218.640 ;
        RECT 4.000 210.480 250.620 217.240 ;
        RECT 4.000 209.080 250.220 210.480 ;
        RECT 4.000 202.320 250.620 209.080 ;
        RECT 4.000 200.920 250.220 202.320 ;
        RECT 4.000 194.160 250.620 200.920 ;
        RECT 4.000 192.760 250.220 194.160 ;
        RECT 4.000 186.000 250.620 192.760 ;
        RECT 4.000 184.600 250.220 186.000 ;
        RECT 4.000 177.840 250.620 184.600 ;
        RECT 4.000 176.440 250.220 177.840 ;
        RECT 4.000 169.680 250.620 176.440 ;
        RECT 4.000 168.280 250.220 169.680 ;
        RECT 4.000 161.520 250.620 168.280 ;
        RECT 4.000 160.120 250.220 161.520 ;
        RECT 4.000 153.360 250.620 160.120 ;
        RECT 4.000 151.960 250.220 153.360 ;
        RECT 4.000 145.200 250.620 151.960 ;
        RECT 4.000 143.800 250.220 145.200 ;
        RECT 4.000 137.040 250.620 143.800 ;
        RECT 4.000 135.640 250.220 137.040 ;
        RECT 4.000 132.960 250.620 135.640 ;
        RECT 4.400 131.560 250.620 132.960 ;
        RECT 4.000 128.880 250.620 131.560 ;
        RECT 4.000 127.480 250.220 128.880 ;
        RECT 4.000 120.720 250.620 127.480 ;
        RECT 4.000 119.320 250.220 120.720 ;
        RECT 4.000 112.560 250.620 119.320 ;
        RECT 4.000 111.160 250.220 112.560 ;
        RECT 4.000 104.400 250.620 111.160 ;
        RECT 4.000 103.000 250.220 104.400 ;
        RECT 4.000 96.240 250.620 103.000 ;
        RECT 4.000 94.840 250.220 96.240 ;
        RECT 4.000 88.080 250.620 94.840 ;
        RECT 4.000 86.680 250.220 88.080 ;
        RECT 4.000 79.920 250.620 86.680 ;
        RECT 4.000 78.520 250.220 79.920 ;
        RECT 4.000 71.760 250.620 78.520 ;
        RECT 4.000 70.360 250.220 71.760 ;
        RECT 4.000 63.600 250.620 70.360 ;
        RECT 4.000 62.200 250.220 63.600 ;
        RECT 4.000 55.440 250.620 62.200 ;
        RECT 4.000 54.040 250.220 55.440 ;
        RECT 4.000 47.280 250.620 54.040 ;
        RECT 4.000 45.880 250.220 47.280 ;
        RECT 4.000 44.560 250.620 45.880 ;
        RECT 4.400 43.160 250.620 44.560 ;
        RECT 4.000 39.120 250.620 43.160 ;
        RECT 4.000 37.720 250.220 39.120 ;
        RECT 4.000 30.960 250.620 37.720 ;
        RECT 4.000 29.560 250.220 30.960 ;
        RECT 4.000 22.800 250.620 29.560 ;
        RECT 4.000 21.400 250.220 22.800 ;
        RECT 4.000 14.640 250.620 21.400 ;
        RECT 4.000 13.240 250.220 14.640 ;
        RECT 4.000 6.480 250.620 13.240 ;
        RECT 4.000 5.615 250.220 6.480 ;
      LAYER met4 ;
        RECT 89.535 13.095 124.320 237.145 ;
        RECT 126.720 13.095 127.620 237.145 ;
        RECT 130.020 13.095 174.320 237.145 ;
        RECT 176.720 13.095 177.620 237.145 ;
        RECT 180.020 13.095 224.320 237.145 ;
        RECT 226.720 13.095 227.620 237.145 ;
        RECT 230.020 13.095 236.145 237.145 ;
  END
END semi_cpu_top
END LIBRARY

